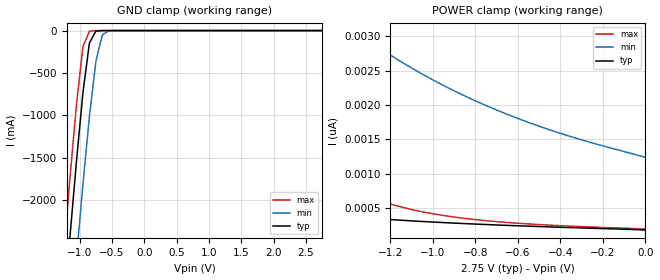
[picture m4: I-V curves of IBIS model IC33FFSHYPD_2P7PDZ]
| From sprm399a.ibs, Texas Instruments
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|   Model IC33FFSHYPD_2P7PDZ
[Model]   IC33FFSHYPD_2P7PDZ
Model_type   Input
Polarity   Non-Inverting
Vinl =   0.8250V
Vinh =   1.9250V
C_comp   2.1397pF   2.1767pF   2.7158pF
[Temperature Range]   25.0000   0.1250k   -40.0000
[Voltage Range]   2.7500V   2.5000V   3.0000V
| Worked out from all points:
|   GND clamp passes 1 mA (typ) near -0.66 V on its own axis
[GND_clamp]
| voltage   I(typ)   I(min)   I(max)
-2.75V    -17.91A    -19.01A    -17.27A
-1.25V    -3.342A    -4.502A    -2.646A
-1.15V    -2.424A    -3.58A     -1.732A
-1.05V    -1.541A    -2.68A     -871.7mA
-950mV    -732.7mA   -1.814A    -188.7mA
-850mV    -147.9mA   -1.014A    -7.751mA
-750mV    -6.008mA   -364.9mA   -798.6uA
-650mV    -206.2uA   -49.97mA   -59.18uA
-550mV    -9.482uA   -3.232mA   -2.615uA
2.75V     180.2pA    1.447nA    169.1pA
[POWER_clamp]
| voltage   I(typ)   I(min)   I(max)
-2.75V    1.397nA    9.158nA    24.63nA
-2.4V     920.9pA    6.881nA    9.413nA
-2V       610.6pA    4.999nA    3.236nA
-1.95V    583.2pA    4.806nA    2.845nA
-1.8V     511.3pA    4.276nA    1.953nA
-1.7V     471pA      3.959nA    1.536nA
-1.55V    420pA      3.532nA    1.094nA
-1.35V    365.5pA    3.042nA    728pA
-1.1V     313.7pA    2.538nA    479pA
-750mV    260.3pA    1.992nA    316.3pA
-400mV    220.4pA    1.587nA    243.2pA
0V        180.2pA    1.238nA    193.4pA
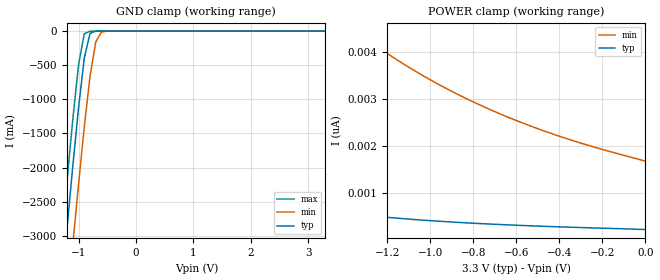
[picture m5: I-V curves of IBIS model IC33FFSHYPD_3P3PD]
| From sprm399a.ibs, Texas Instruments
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|   Model IC33FFSHYPD_3P3PD
[Model]   IC33FFSHYPD_3P3PD
Model_type   Input
Polarity   Non-Inverting
Vinl =   0.9900V
Vinh =   2.3100V
C_comp   2.7290pF   2.5232pF   5.1738pF
[Temperature Range]   25.0000   0.1250k   -40.0000
[Voltage Range]   3.3000V   3.0000V   3.6000V
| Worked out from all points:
|   GND clamp passes 1 mA (typ) near -0.69 V on its own axis
[GND_clamp]
| voltage   I(typ)   I(min)   I(max)
-3.3V     -23.34A    -24.42A    -22.71A
-1.3V     -3.808A    -4.968A    -3.114A
-1.2V     -2.88A     -4.039A    -2.185A
-1.1V     -1.977A    -3.127A    -1.292A
-1V       -1.123A    -2.241A    -489.8mA
-900mV    -393.5mA   -1.402A    -39.32mA
-800mV    -34.1mA    -660.7mA   -2.407mA
-700mV    -1.07mA    -156.4mA   -232.2uA
-600mV    -43.08uA   -13.13mA   -13.27uA
-400mV    -95.63nA   -46.07uA   -11.78nA
3.3V      233.2pA    2.063nA    221.1pA
[POWER_clamp]
| voltage   I(typ)   I(min)   I(max)
-3.3V     6.524nA    22.06nA    NA
-3.05V    4.505nA    17.86nA    NA
-2.8V     3.139nA    14.47nA    NA
-2.6V     2.372nA    12.24nA    NA
-2.3V     1.589nA    9.546nA    NA
-2V       1.097nA    7.465nA    NA
-1.7V     784.5pA    5.861nA    NA
-1.35V    559.4pA    4.448nA    NA
-1.05V    437.9pA    3.535nA    NA
-750mV    355.9pA    2.83nA     NA
-400mV    290.4pA    2.209nA    NA
0V        233.2pA    1.682nA    NA
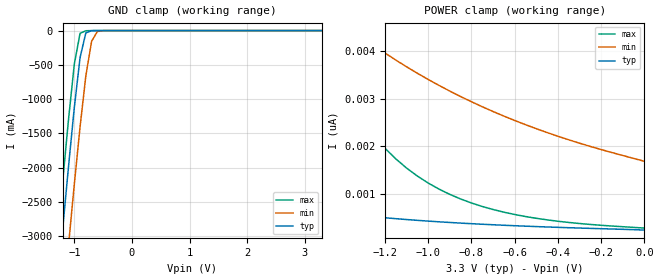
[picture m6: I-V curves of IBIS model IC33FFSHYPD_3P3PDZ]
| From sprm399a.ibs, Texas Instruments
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|   Model IC33FFSHYPD_3P3PDZ
[Model]   IC33FFSHYPD_3P3PDZ
Model_type   Input
Polarity   Non-Inverting
Vinl =   0.9900V
Vinh =   2.3100V
C_comp   2.7290pF   2.5232pF   5.1738pF
[Temperature Range]   25.0000   0.1250k   -40.0000
[Voltage Range]   3.3000V   3.0000V   3.6000V
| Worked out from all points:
|   GND clamp passes 1 mA (typ) near -0.69 V on its own axis
[GND_clamp]
| voltage   I(typ)   I(min)   I(max)
-3.3V     -23.34A    -24.42A    -22.71A
-1.3V     -3.808A    -4.968A    -3.114A
-1.2V     -2.88A     -4.039A    -2.185A
-1.1V     -1.977A    -3.127A    -1.292A
-1V       -1.123A    -2.241A    -489.8mA
-900mV    -393.5mA   -1.402A    -39.31mA
-800mV    -34.1mA    -660.7mA   -2.406mA
-700mV    -1.07mA    -156.4mA   -232.2uA
-600mV    -43.05uA   -13.13mA   -13.27uA
-400mV    -95.62nA   -45.97uA   -11.78nA
3.3V      231.2pA    2.06nA     219pA
[POWER_clamp]
| voltage   I(typ)   I(min)   I(max)
-3.3V     6.522nA    22.06nA    577.8nA
-3.05V    4.503nA    17.86nA    293.1nA
-2.7V     2.724nA    13.31nA    112.3nA
-2.35V    1.693nA    9.946nA    42.79nA
-2V       1.094nA    7.463nA    16.29nA
-1.55V    672.1pA    5.2nA      4.797nA
-1.5V     640.3pA    4.999nA    4.202nA
-1.35V    557.4pA    4.445nA    2.845nA
-1.25V    511.3pA    4.114nA    2.21nA
-1V       420pA      3.402nA    1.221nA
-600mV    322.9pA    2.538nA    559.1pA
0V        231.2pA    1.679nA    272.9pA
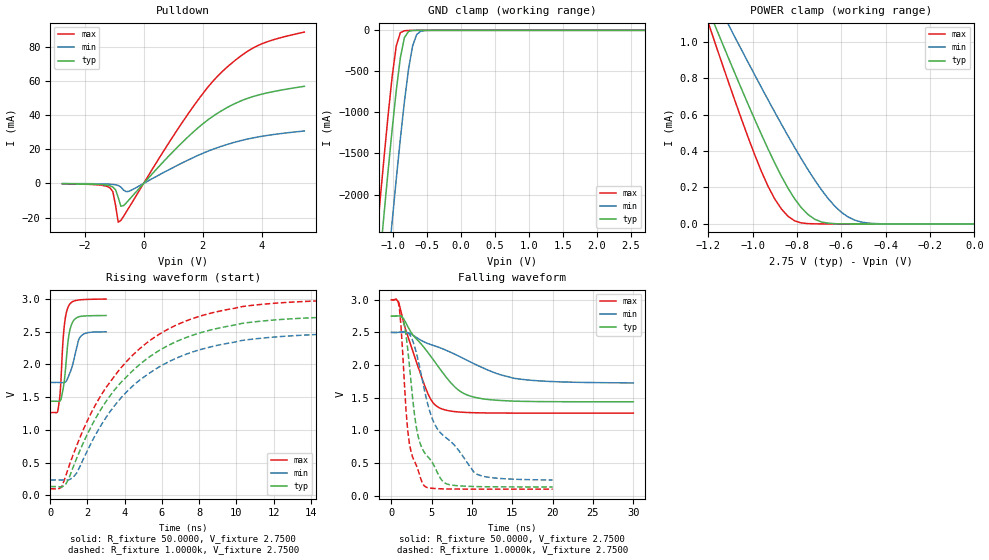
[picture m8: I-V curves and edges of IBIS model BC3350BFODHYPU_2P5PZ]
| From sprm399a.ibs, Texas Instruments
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|   Model BC3350BFODHYPU_2P5PZ
[Model]   BC3350BFODHYPU_2P5PZ
Model_type   I/O_open_drain
Polarity   Non-Inverting
Enable   Active-Low
Vinl =   0.7500V
Vinh =   1.7500V
Vmeas =   1.2500V
Cref =  15.0000pF
Rref = 100.0000M
Vref =  0.000V
C_comp   2.5179pF   2.5239pF   3.1043pF
[Temperature Range]   25.0000   0.1250k   -40.0000
[Voltage Range]   2.7500V   2.5000V   3.0000V
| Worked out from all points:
|   slope of the pulldown table from 0 to 0.412 V, typ, clamps not added: 52.2 ohm
|   GND clamp passes 1 mA (typ) near -0.68 V on its own axis
|   POWER clamp passes 1 mA (typ) near -1.14 V on its own axis
|   rising waveform, R_fixture 50.0000, V_fixture 2.7500: 20-80 % time 293ps typ, 424ps min, 236ps max; typ from 1.44 V to 2.75 V
|   rising waveform, R_fixture 1.0000k, V_fixture 2.7500: 20-80 % time 4.36ns typ, 4.36ns min, 4.3ns max; typ from 0.135 V to 2.74 V
|   falling waveform, R_fixture 50.0000, V_fixture 2.7500: 20-80 % time 5.07ns typ, 8.6ns min, 2.85ns max; typ from 2.75 V to 1.44 V
|   falling waveform, R_fixture 1.0000k, V_fixture 2.7500: 20-80 % time 2.08ns typ, 4.99ns min, 1.15ns max; typ from 2.75 V to 0.135 V
[Pulldown]
| voltage   I(typ)   I(min)   I(max)
-2.75V    -196uA     -89uA      -273uA
-1.13V    -1.446mA   -462.7uA   -2.767mA
-1.04V    -2.119mA   -590.9uA   -4.941mA
-950mV    -3.685mA   -805.5uA   -12.8mA
-860mV    -8.252mA   -1.217mA   -22.69mA
-770mV    -13.34mA   -2.137mA   -21.65mA
-680mV    -13.04mA   -3.916mA   -19.29mA
-410mV    -7.97mA    -3.938mA   -11.68mA
1.3V      23.88mA    11.95mA    35.5mA
2.56V     41.71mA    21.31mA    63.75mA
3.82V     51.42mA    27.03mA    80.29mA
5.44V     56.82mA    30.68mA    88.57mA
[GND_clamp]
| voltage   I(typ)   I(min)   I(max)
-2.75V    -17.91A    -19.01A    -17.27A
-1.25V    -3.342A    -4.502A    -2.647A
-1.19V    -2.788A    -3.947A    -2.094A
-1.13V    -2.244A    -3.398A    -1.555A
-1.01V    -1.205A    -2.328A    -562.5mA
-950mV    -733.5mA   -1.814A    -190.1mA
-890mV    -336.3mA   -1.323A    -28.95mA
-830mV    -88.34mA   -867.9mA   -5.22mA
-770mV    -13.12mA   -475.3mA   -1.386mA
-710mV    -1.827mA   -190.8mA   -326.2uA
-590mV    -39.46uA   -10.65mA   -10.29uA
2.71V     264.7pA    4.348nA    254.9pA
[POWER_clamp]
| voltage   I(typ)   I(min)   I(max)
-2.73V    5.917mA    5.089mA    6.919mA
-1.2V     1.179mA    1.31mA     1.105mA
-1.17V    1.09mA     1.238mA    996.2uA
-1.11V    914uA      1.096mA    782.5uA
-1.08V    827uA      1.026mA    677.7uA
-990mV    572.4uA    816.8uA    378.4uA
-900mV    334.2uA    613.4uA    137uA
-810mV    137.3uA    418.9uA    16.8uA
-720mV    26.09uA    241.1uA    664.2nA
-600mV    534.9nA    64.48uA    19.7nA
-510mV    25.5nA     10.6uA     1.291nA
0V        271.3pA    1.545nA    292.4pA
[Ramp]
| variable   typ   min   max
dV/dt_r   0.2317n/0.1893f  33.7855p/0.3440n   0.1839n/0.1188f
dV/dt_f   0.7869/5.0163n   0.4633/8.5159n   1.0409/2.8255n
R_load = 50.0000
[Rising Waveform]
R_fixture = 50.0000
V_fixture = 2.7500
V_fixture_min = 2.5000
V_fixture_max = 3.0000
| time   V(typ)   V(min)   V(max)
0s        1.438V     1.725V     1.265V
424.2ps   1.436V     1.725V     1.319V
545.5ps   1.448V     1.724V     1.617V
666.7ps   1.593V     1.722V     2.285V
727.3ps   1.691V     1.722V     2.516V
818.2ps   1.928V     1.732V     2.725V
969.7ps   2.388V     1.812V     2.884V
1.212ns   2.652V     2.008V     2.961V
1.636ns   2.733V     2.428V     2.987V
3ns       2.747V     2.498V     2.998V
[Rising Waveform]
R_fixture = 1.0000k
V_fixture = 2.7500
V_fixture_min = 2.5000
V_fixture_max = 3.0000
| time   V(typ)   V(min)   V(max)
0s        134.8mV    236.4mV    101.3mV
606.1ps   128.5mV    236.5mV    124.7mV
808.1ps   156.8mV    234.3mV    279.7mV
1.212ns   418.4mV    271.3mV    608.1mV
2.222ns   1.066V     814.6mV    1.273V
3.434ns   1.604V     1.363V     1.816V
4.848ns   2.01V      1.77V      2.251V
6.465ns   2.307V     2.055V     2.558V
10.91ns   2.648V     2.387V     2.904V
20ns      2.744V     2.491V     2.995V
[Falling Waveform]
R_fixture = 50.0000
V_fixture = 2.7500
V_fixture_min = 2.5000
V_fixture_max = 3.0000
| time   V(typ)   V(min)   V(max)
0s        2.75V      2.5V       3V
909.1ps   2.753V     2.502V     2.963V
1.818ns   2.644V     2.5V       2.524V
4.242ns   2.241V     2.345V     1.651V
5.152ns   2.091V     2.304V     1.427V
6.061ns   1.936V     2.264V     1.339V
8.485ns   1.603V     2.129V     1.282V
11.21ns   1.486V     1.965V     1.269V
16.67ns   1.445V     1.776V     1.265V
30ns      1.438V     1.728V     1.265V
[Falling Waveform]
R_fixture = 1.0000k
V_fixture = 2.7500
V_fixture_min = 2.5000
V_fixture_max = 3.0000
| time   V(typ)   V(min)   V(max)
0s        2.75V      2.5V       3V
1.01ns    2.762V     2.503V     2.859V
1.616ns   2.617V     2.51V      1.728V
2.222ns   2.019V     2.476V     812.9mV
3.03ns    1.102V     2.22V      485.3mV
4.04ns    674.1mV    1.654V     157.4mV
5.657ns   368.4mV    1.035V     109.5mV
6.869ns   182mV      880.4mV    104.9mV
10.3ns    141.5mV    354.1mV    101.8mV
20ns      135mV      241.6mV    101.3mV
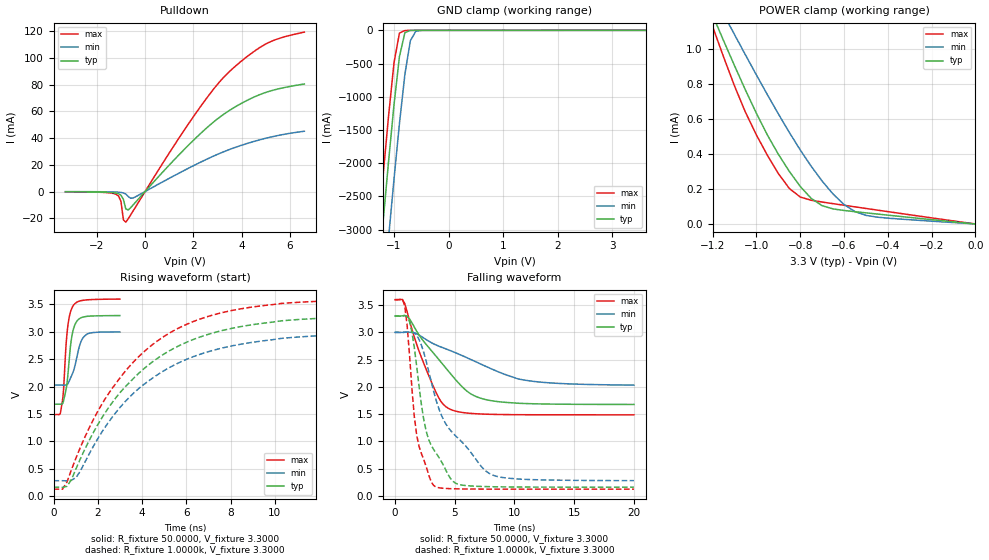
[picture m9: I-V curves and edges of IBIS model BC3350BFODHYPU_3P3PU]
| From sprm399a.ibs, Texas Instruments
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|   Model BC3350BFODHYPU_3P3PU
[Model]   BC3350BFODHYPU_3P3PU
Model_type   I/O_open_drain
Polarity   Non-Inverting
Enable   Active-Low
Vinl =   0.9900V
Vinh =   2.3100V
Vmeas =   1.6500V
Cref =  15.0000pF
Rref = 100.0000M
Vref =  0.000V
C_comp   3.1345pF   2.9748pF   5.4957pF
[Temperature Range]   25.0000   0.1250k   -40.0000
[Voltage Range]   3.3000V   3.0000V   3.6000V
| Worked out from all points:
|   slope of the pulldown table from 0 to 0.495 V, typ, clamps not added: 49.9 ohm
|   GND clamp passes 1 mA (typ) near -0.66 V on its own axis
|   POWER clamp passes 1 mA (typ) near -1.13 V on its own axis
|   rising waveform, R_fixture 50.0000, V_fixture 3.3000: 20-80 % time 267ps typ, 384ps min, 224ps max; typ from 1.68 V to 3.3 V
|   rising waveform, R_fixture 1.0000k, V_fixture 3.3000: 20-80 % time 3.97ns typ, 4.07ns min, 3.81ns max; typ from 0.162 V to 3.3 V
|   falling waveform, R_fixture 50.0000, V_fixture 3.3000: 20-80 % time 3.68ns typ, 6.15ns min, 2.15ns max; typ from 3.3 V to 1.68 V
|   falling waveform, R_fixture 1.0000k, V_fixture 3.3000: 20-80 % time 1.78ns typ, 3.63ns min, 1.05ns max; typ from 3.3 V to 0.162 V
[Pulldown]
| voltage   I(typ)   I(min)   I(max)
-3.3V     -159uA     -74uA      -216uA
-1.2V     -1.209mA   -418.8uA   -2.097mA
-1V       -2.765mA   -711.7uA   -7.396mA
-900mV    -5.896mA   -1.056mA   -21.15mA
-800mV    -13.01mA   -1.838mA   -22.95mA
-700mV    -13.84mA   -3.683mA   -20.42mA
-500mV    -10.11mA   -4.828mA   -14.63mA
1.7V      32.91mA    16.52mA    48.03mA
3.2V      57.06mA    29.34mA    84.35mA
4.1V      67.02mA    35.22mA    99.18mA
5V        74.15mA    39.85mA    110.4mA
6.6V      80.46mA    45.12mA    119.3mA
[GND_clamp]
| voltage   I(typ)   I(min)   I(max)
-3.3V     -23.34A    -24.42A    -22.71A
-1.3V     -3.808A    -4.968A    -3.114A
-1.2V     -2.88A     -4.039A    -2.186A
-1.1V     -1.977A    -3.127A    -1.292A
-1V       -1.123A    -2.241A    -490.8mA
-900mV    -394.6mA   -1.403A    -40.99mA
-800mV    -35.51mA   -661.5mA   -2.889mA
-700mV    -1.457mA   -157.5mA   -462.5uA
-600mV    -189.6uA   -13.98mA   -225uA
-400mV    -135.5uA   -145.8uA   -210.3uA
3.62V     0A         0A         0A
[POWER_clamp]
| voltage   I(typ)   I(min)   I(max)
-3.3V     7.712mA    6.522mA    9.121mA
-1.2V     1.191mA    1.315mA    1.126mA
-1.15V    1.045mA    1.197mA    952.4uA
-1.1V     902.5uA    1.08mA     787uA
-1V       630.6uA    849.8uA    507.3uA
-900mV    397.7uA    628uA      287.6uA
-850mV    300uA      522.4uA    202.7uA
-750mV    145.8uA    329.1uA    135.2uA
-650mV    85.85uA    170.4uA    115.8uA
-550mV    69.94uA    70.52uA    97.52uA
-450mV    56.73uA    38.93uA    79.36uA
0V        339.2pA    2.034nA    390pA
[Ramp]
| variable   typ   min   max
dV/dt_r   2.0284m/0.4301n   0.8263m/0.3985n   3.7339m/0.4501n
dV/dt_f   0.9733/3.6469n   0.5839/6.1478n   1.2669/2.1300n
R_load = 50.0000
[Rising Waveform]
R_fixture = 50.0000
V_fixture = 3.3000
V_fixture_min = 3.0000
V_fixture_max = 3.6000
| time   V(typ)   V(min)   V(max)
0s        1.678V     2.026V     1.488V
333.3ps   1.676V     2.026V     1.564V
454.5ps   1.738V     2.025V     1.951V
545.5ps   1.905V     2.026V     2.631V
636.4ps   2.159V     2.044V     3.074V
757.6ps   2.704V     2.147V     3.349V
878.8ps   3.016V     2.258V     3.47V
1.212ns   3.25V      2.791V     3.566V
1.424ns   3.277V     2.929V     3.58V
3ns       3.297V     2.997V     3.598V
[Rising Waveform]
R_fixture = 1.0000k
V_fixture = 3.3000
V_fixture_min = 3.0000
V_fixture_max = 3.6000
| time   V(typ)   V(min)   V(max)
0s        161.7mV    279.7mV    125.2mV
404ps     157.5mV    279.9mV    125.1mV
606.1ps   176.3mV    276.5mV    254.2mV
1.01ns    492.5mV    334.1mV    689mV
2.02ns    1.318V     1.061V     1.562V
3.232ns   1.991V     1.722V     2.274V
4.444ns   2.442V     2.145V     2.757V
6.061ns   2.817V     2.505V     3.144V
10.3ns    3.201V     2.88V      3.518V
20ns      3.297V     2.993V     3.598V
[Falling Waveform]
R_fixture = 50.0000
V_fixture = 3.3000
V_fixture_min = 3.0000
V_fixture_max = 3.6000
| time   V(typ)   V(min)   V(max)
0s        3.3V       3V         3.6V
808.1ps   3.304V     3.002V     3.531V
1.818ns   3.019V     2.974V     2.776V
3.232ns   2.616V     2.79V      1.995V
3.838ns   2.457V     2.732V     1.736V
4.646ns   2.242V     2.664V     1.587V
6.263ns   1.884V     2.511V     1.516V
8.081ns   1.747V     2.33V      1.497V
11.72ns   1.691V     2.099V     1.49V
20ns      1.678V     2.033V     1.488V
[Falling Waveform]
R_fixture = 1.0000k
V_fixture = 3.3000
V_fixture_min = 3.0000
V_fixture_max = 3.6000
| time   V(typ)   V(min)   V(max)
0s        3.3V       3V         3.6V
808.1ps   3.312V     3.003V     3.491V
1.212ns   3.2V       3.01V      2.591V
1.616ns   2.719V     2.991V     1.449V
1.818ns   2.37V      2.946V     1.109V
2.424ns   1.377V     2.619V     656.3mV
3.232ns   851.5mV    1.92V      192.6mV
5.051ns   237mV      1.107V     131.7mV
8.081ns   170.1mV    392.5mV    126.1mV
20ns      161.8mV    281.5mV    125.2mV
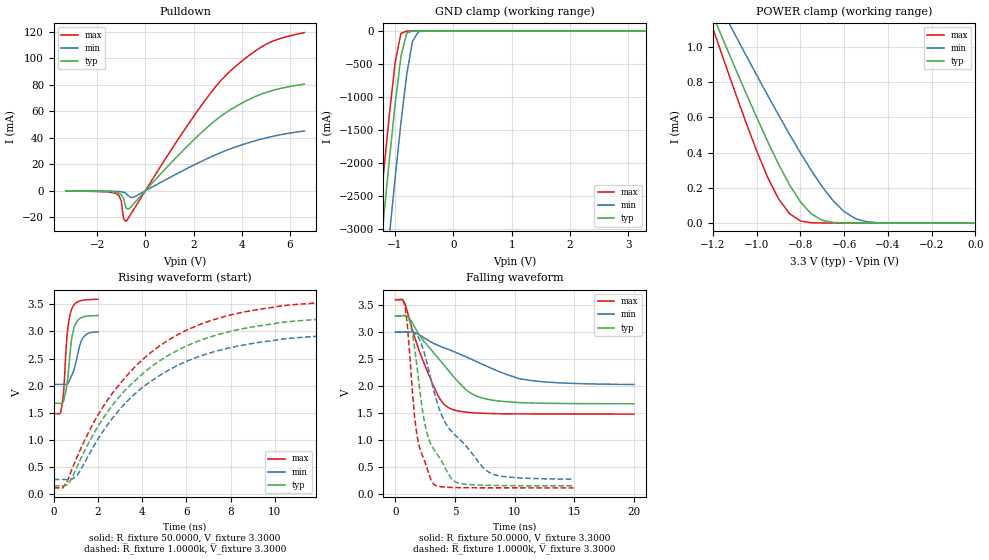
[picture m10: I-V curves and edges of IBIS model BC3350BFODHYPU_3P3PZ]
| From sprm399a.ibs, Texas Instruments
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|   Model BC3350BFODHYPU_3P3PZ
[Model]   BC3350BFODHYPU_3P3PZ
Model_type   I/O_open_drain
Polarity   Non-Inverting
Enable   Active-Low
Vinl =   0.9900V
Vinh =   2.3100V
Vmeas =   1.6500V
Cref =  15.0000pF
Rref = 100.0000M
Vref =  0.000V
C_comp   3.1345pF   2.9748pF   5.4957pF
[Temperature Range]   25.0000   0.1250k   -40.0000
[Voltage Range]   3.3000V   3.0000V   3.6000V
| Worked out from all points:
|   slope of the pulldown table from 0 to 0.495 V, typ, clamps not added: 49.9 ohm
|   GND clamp passes 1 mA (typ) near -0.67 V on its own axis
|   POWER clamp passes 1 mA (typ) near -1.14 V on its own axis
|   rising waveform, R_fixture 50.0000, V_fixture 3.3000: 20-80 % time 267ps typ, 381ps min, 224ps max; typ from 1.68 V to 3.29 V
|   rising waveform, R_fixture 1.0000k, V_fixture 3.3000: 20-80 % time 4.3ns typ, 4.29ns min, 4.24ns max; typ from 0.155 V to 3.29 V
|   falling waveform, R_fixture 50.0000, V_fixture 3.3000: 20-80 % time 3.68ns typ, 6.15ns min, 2.15ns max; typ from 3.3 V to 1.68 V
|   falling waveform, R_fixture 1.0000k, V_fixture 3.3000: 20-80 % time 1.73ns typ, 3.57ns min, 1.02ns max; typ from 3.3 V to 0.156 V
[Pulldown]
| voltage   I(typ)   I(min)   I(max)
-3.3V     -159uA     -74uA      -215uA
-1.2V     -1.209mA   -418.8uA   -2.097mA
-1V       -2.765mA   -711.8uA   -7.394mA
-900mV    -5.895mA   -1.056mA   -21.15mA
-800mV    -13mA      -1.838mA   -22.95mA
-700mV    -13.84mA   -3.683mA   -20.42mA
-500mV    -10.11mA   -4.828mA   -14.63mA
1.7V      32.91mA    16.52mA    48.03mA
3.2V      57.06mA    29.34mA    84.35mA
4.1V      67.02mA    35.22mA    99.19mA
5V        74.15mA    39.85mA    110.4mA
6.6V      80.46mA    45.12mA    119.3mA
[GND_clamp]
| voltage   I(typ)   I(min)   I(max)
-3.3V     -23.34A    -24.42A    -22.71A
-1.3V     -3.808A    -4.968A    -3.114A
-1.2V     -2.88A     -4.039A    -2.186A
-1.1V     -1.977A    -3.127A    -1.292A
-1V       -1.123A    -2.241A    -490.7mA
-900mV    -394.6mA   -1.403A    -40.81mA
-800mV    -35.4mA    -661.4mA   -2.68mA
-700mV    -1.323mA   -157.5mA   -251.4uA
-600mV    -53.86uA   -13.9mA    -14.12uA
-400mV    -110.6nA   -62.84uA   -12.31nA
3.3V      340.8pA    35.66nA    327pA
[POWER_clamp]
| voltage   I(typ)   I(min)   I(max)
-3.3V     7.71mA     6.521mA    9.119mA
-1.2V     1.179mA    1.31mA     1.105mA
-1.15V    1.031mA    1.191mA    924.5uA
-1.1V     884.9uA    1.073mA    747.4uA
-950mV    463.6uA    725.5uA    259.4uA
-900mV    334.2uA    613.4uA    137uA
-850mV    216.9uA    503.9uA    53.53uA
-800mV    120.1uA    398.1uA    11.85uA
-700mV    15.1uA     205.4uA    362.5nA
-600mV    535nA      64.48uA    20nA
-550mV    96.74nA    26.14uA    4.477nA
0V        340.8pA    2.036nA    391.7pA
[Ramp]
| variable   typ   min   max
dV/dt_r   0.2240n/0.1170f  0.1219n/0.1041f  0.1534n/4.2679n
dV/dt_f   0.9752/3.6442n   0.5851/6.1456n   1.2694/2.1275n
R_load = 50.0000
[Rising Waveform]
R_fixture = 50.0000
V_fixture = 3.3000
V_fixture_min = 3.0000
V_fixture_max = 3.6000
| time   V(typ)   V(min)   V(max)
|  0.000S   1.6747V   2.0242V   1.4843V
30.3ps    1.675V     2.024V     1.484V
303ps     1.673V     2.024V     1.501V
393.9ps   1.679V     2.023V     1.71V
454.5ps   1.735V     2.022V     1.945V
545.5ps   1.901V     2.023V     2.625V
606.1ps   2.046V     2.031V     2.952V
787.9ps   2.804V     2.172V     3.386V
969.7ps   3.127V     2.379V     3.514V
1.303ns   3.264V     2.87V      3.573V
2ns       3.292V     2.992V     3.592V
[Rising Waveform]
R_fixture = 1.0000k
V_fixture = 3.3000
V_fixture_min = 3.0000
V_fixture_max = 3.6000
| time   V(typ)   V(min)   V(max)
0s        155.4mV    272.2mV    118.3mV
404ps     151.2mV    272.5mV    116.9mV
606.1ps   168.3mV    269mV      236.1mV
1.01ns    470mV      324.2mV    646.5mV
2.02ns    1.264V     1.03V      1.474V
3.232ns   1.919V     1.676V     2.152V
4.646ns   2.418V     2.15V      2.692V
6.263ns   2.777V     2.491V     3.069V
10.71ns   3.183V     2.873V     3.488V
20ns      3.294V     2.99V      3.595V
[Falling Waveform]
R_fixture = 50.0000
V_fixture = 3.3000
V_fixture_min = 3.0000
V_fixture_max = 3.6000
| time   V(typ)   V(min)   V(max)
0s        3.3V       3V         3.6V
808.1ps   3.304V     3.002V     3.531V
1.818ns   3.018V     2.974V     2.772V
3.232ns   2.614V     2.789V     1.99V
3.838ns   2.454V     2.732V     1.731V
4.646ns   2.239V     2.663V     1.583V
6.263ns   1.881V     2.51V      1.512V
8.081ns   1.744V     2.328V     1.493V
11.72ns   1.687V     2.097V     1.485V
20ns      1.675V     2.031V     1.484V
[Falling Waveform]
R_fixture = 1.0000k
V_fixture = 3.3000
V_fixture_min = 3.0000
V_fixture_max = 3.6000
| time   V(typ)   V(min)   V(max)
0s        3.3V       3V         3.6V
808.1ps   3.312V     3.003V     3.491V
1.212ns   3.2V       3.01V      2.58V
1.616ns   2.714V     2.991V     1.426V
1.818ns   2.36V      2.945V     1.085V
2.424ns   1.357V     2.615V     632.8mV
3.232ns   828.7mV    1.907V     182.7mV
5.051ns   227.2mV    1.087V     124.6mV
7.879ns   164.4mV    403.9mV    119.3mV
14.95ns   155.8mV    279.1mV    118.3mV
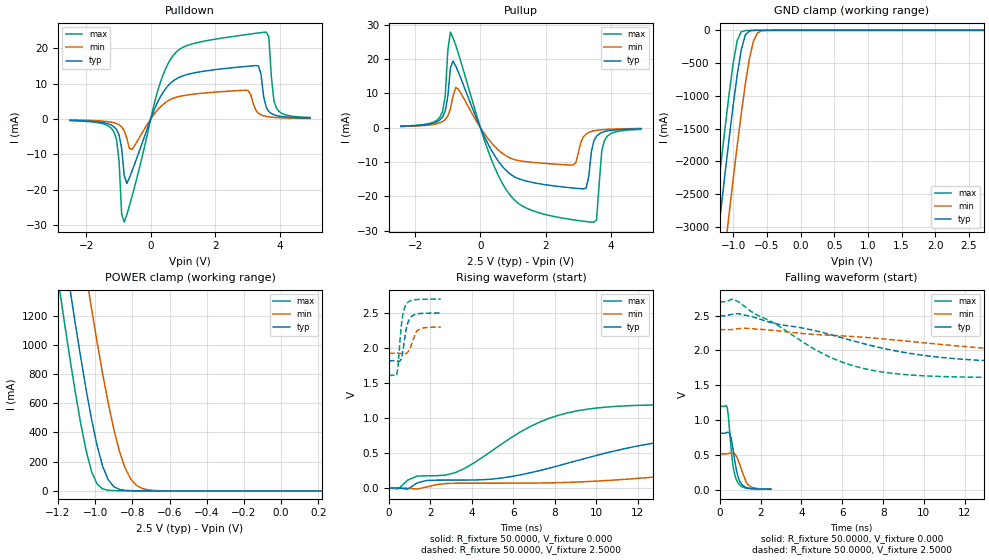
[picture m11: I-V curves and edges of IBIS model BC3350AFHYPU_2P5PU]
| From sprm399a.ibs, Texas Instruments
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|   Model BC3350AFHYPU_2P5PU
[Model]   BC3350AFHYPU_2P5PU
Model_type   I/O
Polarity   Non-Inverting
Enable   Active-Low
Vinl =   0.7500V
Vinh =   1.7500V
Vmeas =   1.2500V
Cref =  15.0000pF
Rref = 100.0000M
Vref =  0.000V
C_comp   2.5606pF   2.5670pF   2.5554pF
[Temperature Range]   25.0000   0.1250k   -40.0000
[Voltage Range]   2.5000V   2.3000V   2.7000V
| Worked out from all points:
|   slope of the pulldown table from 0 to 0.375 V, typ, clamps not added: 50.5 ohm
|   slope of the pullup table from 0 to 0.375 V, typ, clamps not added: 52.4 ohm
|   GND clamp passes 1 mA (typ) near -0.69 V on its own axis
|   POWER clamp passes 1 mA (typ) near -0.78 V on its own axis
|   rising waveform, R_fixture 50.0000, V_fixture 0.000: 20-80 % time 7.03ns typ, 12.5ns min, 4.06ns max; typ from 0.001 V to 0.809 V
|   rising waveform, R_fixture 50.0000, V_fixture 2.5000: 20-80 % time 245ps typ, 281ps min, 211ps max; typ from 1.82 V to 2.5 V
|   falling waveform, R_fixture 50.0000, V_fixture 0.000: 20-80 % time 303ps typ, 381ps min, 259ps max; typ from 0.809 V to 0.005 V
|   falling waveform, R_fixture 50.0000, V_fixture 2.5000: 20-80 % time 6.26ns typ, 9.67ns min, 4ns max; typ from 2.5 V to 1.82 V
[Pulldown]
| voltage   I(typ)   I(min)   I(max)
-2.5V     -374uA     -257uA     -456uA
-1.14V    -2.171mA   -1.061mA   -3.627mA
-980mV    -4.503mA   -1.644mA   -11.87mA
-820mV    -15.98mA   -3.315mA   -29.14mA
-580mV    -14.72mA   -8.608mA   -21.9mA
300mV     6.273mA    3.423mA    10.36mA
940mV     12mA       6.481mA    19.96mA
3.02V     14.92mA    8.019mA    23.92mA
3.34V     15mA       1.628mA    24.32mA
3.58V     3.34mA     742.8uA    24.56mA
3.9V      981uA      418uA      3.045mA
4.94V     280uA      169uA      430uA
[Pullup]
| voltage   I(typ)   I(min)   I(max)
-2.44V    429uA      355uA      471uA
-1.24V    2.302mA    1.467mA    3.141mA
-1.08V    4.893mA    2.412mA    9.263mA
-920mV    17.47mA    5.496mA    27.87mA
-680mV    16.28mA    11.27mA    21.75mA
440mV     -8.176mA   -5.47mA    -11.64mA
1.4V      -15.51mA   -9.865mA   -23.35mA
2.84V     -17.54mA   -10.83mA   -26.8mA
3.24V     -17.6mA    -1.801mA   -27.32mA
3.48V     -3.754mA   -895.8uA   -27.51mA
3.8V      -1.135mA   -524.2uA   -3.76mA
4.92V     -310uA     -210uA     -458uA
[GND_clamp]
| voltage   I(typ)   I(min)   I(max)
-2.5V     -15.48A    -16.59A    -14.82A
-1.3V     -3.836A    -5.005A    -3.135A
-1.24V    -3.276A    -4.446A    -2.575A
-1.18V    -2.724A    -3.891A    -2.024A
-1.12V    -2.181A    -3.344A    -1.486A
-1.06V    -1.653A    -2.804A    -972.8mA
-940mV    -681.3mA   -1.763A    -154.8mA
-880mV    -296.6mA   -1.275A    -21.34mA
-820mV    -70.8mA    -824.4mA   -4.046mA
-700mV    -1.244mA   -169.1mA   -348.3uA
-580mV    -94.36uA   -8.425mA   -115.6uA
2.72V     0A         0A         0A
[POWER_clamp]
| voltage   I(typ)   I(min)   I(max)
-2.49V    14.32A     15.09A     13.9A
-1.2V     1.938A     2.775A     1.451A
-1.17V    1.676A     2.51A      1.19A
-1.14V    1.419A     2.247A     938.4mA
-1.11V    1.169A     1.989A     698.1mA
-1.05V    700.4mA    1.489A     281.6mA
-1.02V    491.6mA    1.249A     133.5mA
-960mV    168.5mA    801.5mA    14.02mA
-930mV    76mA       600.7mA    4.535mA
-840mV    3.983mA    158.9mA    893.4uA
-780mV    921.1uA    39.8mA     480.6uA
220mV     0A         0A         0A
[Ramp]
| variable   typ   min   max
dV/dt_r   0.2848/7.3030n   60.7008m/6.6251n  0.6851/3.7184n
dV/dt_f   0.3451/5.0572n   0.1157/5.2443n   0.6386/3.8070n
R_load = 50.0000
[Rising Waveform]
R_fixture = 50.0000
V_fixture = 0.000
V_fixture_min = 0.000
V_fixture_max = 0.000
| time   V(typ)   V(min)   V(max)
0s        1.49mV     1.262mV    1.706mV
454.5ps   2.168mV    1.584mV    -9.699mV
1.364ns   75.35mV    -11.7mV    172.1mV
3.182ns   115.4mV    70.43mV    220.2mV
7.727ns   285.4mV    76.01mV    996.2mV
10.45ns   500.7mV    108.5mV    1.156V
14.09ns   697.7mV    192.6mV    1.192V
18.64ns   784.6mV    317.2mV    1.195V
27.73ns   808.2mV    470.5mV    1.195V
45ns      809.1mV    511.9mV    1.195V
[Rising Waveform]
R_fixture = 50.0000
V_fixture = 2.5000
V_fixture_min = 2.3000
V_fixture_max = 2.7000
| time   V(typ)   V(min)   V(max)
0s        1.816V     1.924V     1.609V
378.8ps   1.814V     1.924V     1.624V
454.5ps   1.809V     1.924V     1.777V
555.6ps   1.821V     1.922V     2.18V
631.3ps   1.886V     1.92V      2.392V
732.3ps   2.067V     1.917V     2.546V
858.6ps   2.299V     1.925V     2.631V
1.061ns   2.439V     2.023V     2.675V
1.389ns   2.487V     2.25V      2.69V
2.5ns     2.497V     2.297V     2.697V
[Falling Waveform]
R_fixture = 50.0000
V_fixture = 0.000
V_fixture_min = 0.000
V_fixture_max = 0.000
| time   V(typ)   V(min)   V(max)
0s        809.1mV    513.8mV    1.195V
353.5ps   819mV      514.9mV    1.191V
429.3ps   823.1mV    518.5mV    1.038V
505.1ps   794.1mV    522.8mV    779.3mV
656.6ps   572.2mV    524mV      332.3mV
757.6ps   383.5mV    503.9mV    191.9mV
883.8ps   198.6mV    436.5mV    102.2mV
1.086ns   74.01mV    270.8mV    41.99mV
1.414ns   19.98mV    62.24mV    13.98mV
2.5ns     5.319mV    5.064mV    5.445mV
[Falling Waveform]
R_fixture = 50.0000
V_fixture = 2.5000
V_fixture_min = 2.3000
V_fixture_max = 2.7000
| time   V(typ)   V(min)   V(max)
0s        2.5V       2.3V       2.7V
606.1ps   2.521V     2.3V       2.739V
909.1ps   2.53V      2.314V     2.702V
2.727ns   2.386V     2.286V     2.381V
4.546ns   2.293V     2.232V     2.036V
5.758ns   2.201V     2.213V     1.859V
8.182ns   2.019V     2.162V     1.681V
11.21ns   1.89V      2.076V     1.623V
15.15ns   1.831V     1.988V     1.61V
30ns      1.816V     1.925V     1.609V
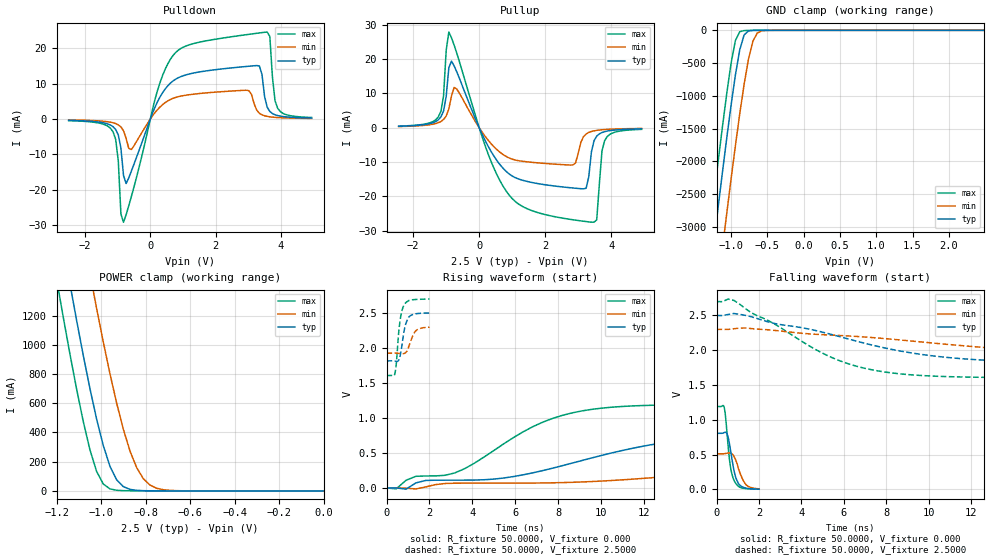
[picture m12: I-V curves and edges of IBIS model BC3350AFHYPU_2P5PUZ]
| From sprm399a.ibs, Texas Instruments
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|   Model BC3350AFHYPU_2P5PUZ
[Model]   BC3350AFHYPU_2P5PUZ
Model_type   I/O
Polarity   Non-Inverting
Enable   Active-Low
Vinl =   0.7500V
Vinh =   1.7500V
Vmeas =   1.2500V
Cref =  15.0000pF
Rref = 100.0000M
Vref =  0.000V
C_comp   2.5606pF   2.5670pF   2.5554pF
[Temperature Range]   25.0000   0.1250k   -40.0000
[Voltage Range]   2.5000V   2.3000V   2.7000V
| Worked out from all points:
|   slope of the pulldown table from 0 to 0.375 V, typ, clamps not added: 50.5 ohm
|   slope of the pullup table from 0 to 0.375 V, typ, clamps not added: 52.4 ohm
|   GND clamp passes 1 mA (typ) near -0.69 V on its own axis
|   POWER clamp passes 1 mA (typ) near -0.79 V on its own axis
|   rising waveform, R_fixture 50.0000, V_fixture 0.000: 20-80 % time 7.01ns typ, 12.4ns min, 4.04ns max; typ from 0 V to 0.806 V
|   rising waveform, R_fixture 50.0000, V_fixture 2.5000: 20-80 % time 243ps typ, 289ps min, 211ps max; typ from 1.81 V to 2.5 V
|   falling waveform, R_fixture 50.0000, V_fixture 0.000: 20-80 % time 300ps typ, 378ps min, 257ps max; typ from 0.806 V to 0.004 V
|   falling waveform, R_fixture 50.0000, V_fixture 2.5000: 20-80 % time 6.26ns typ, 9.37ns min, 4ns max; typ from 2.5 V to 1.81 V
[Pulldown]
| voltage   I(typ)   I(min)   I(max)
-2.5V     -374uA     -257uA     -455uA
-1.14V    -2.171mA   -1.061mA   -3.627mA
-980mV    -4.503mA   -1.644mA   -11.87mA
-820mV    -15.98mA   -3.314mA   -29.14mA
-580mV    -14.72mA   -8.608mA   -21.9mA
300mV     6.272mA    3.423mA    10.36mA
940mV     12mA       6.481mA    19.96mA
3.02V     14.92mA    8.019mA    23.92mA
3.34V     15mA       1.628mA    24.32mA
3.58V     3.34mA     742.8uA    24.56mA
3.9V      980.9uA    418uA      3.045mA
4.94V     280uA      169uA      430uA
[Pullup]
| voltage   I(typ)   I(min)   I(max)
-2.44V    429uA      356uA      472uA
-1.24V    2.302mA    1.467mA    3.141mA
-1.08V    4.893mA    2.412mA    9.262mA
-920mV    17.47mA    5.496mA    27.87mA
-680mV    16.28mA    11.27mA    21.75mA
440mV     -8.177mA   -5.47mA    -11.64mA
1.4V      -15.51mA   -9.865mA   -23.35mA
2.84V     -17.54mA   -10.83mA   -26.8mA
3.24V     -17.6mA    -1.801mA   -27.32mA
3.48V     -3.754mA   -895.8uA   -27.51mA
3.8V      -1.135mA   -524.1uA   -3.76mA
4.92V     -311uA     -209uA     -458uA
[GND_clamp]
| voltage   I(typ)   I(min)   I(max)
-2.5V     -15.48A    -16.59A    -14.82A
-1.3V     -3.836A    -5.005A    -3.135A
-1.24V    -3.276A    -4.446A    -2.575A
-1.18V    -2.724A    -3.891A    -2.024A
-1.12V    -2.181A    -3.344A    -1.486A
-1.06V    -1.653A    -2.804A    -972.7mA
-940mV    -681.3mA   -1.763A    -154.7mA
-880mV    -296.6mA   -1.275A    -21.25mA
-820mV    -70.75mA   -824.4mA   -3.94mA
-700mV    -1.177mA   -169.1mA   -239.8uA
-580mV    -25.2uA    -8.386mA   -7.201uA
2.48V     178pA      15.04nA    165.8pA
[POWER_clamp]
| voltage   I(typ)   I(min)   I(max)
-2.49V    14.32A     15.09A     13.9A
-1.2V     1.938A     2.775A     1.451A
-1.17V    1.676A     2.51A      1.19A
-1.14V    1.419A     2.247A     938.4mA
-1.11V    1.169A     1.989A     698.1mA
-1.05V    700.4mA    1.489A     281.6mA
-1.02V    491.6mA    1.249A     133.5mA
-960mV    168.5mA    801.5mA    13.92mA
-930mV    75.96mA    600.7mA    4.42mA
-840mV    3.915mA    158.9mA    769.8uA
-780mV    843uA      39.78mA    364.7uA
0V        181pA      1.191nA    191.2pA
[Ramp]
| variable   typ   min   max
dV/dt_r   0.2839/7.2876n   60.1978m/6.6356n  0.6835/3.7009n
dV/dt_f   0.3463/5.0576n   0.1160/5.2440n   0.6411/3.8076n
R_load = 50.0000
[Rising Waveform]
R_fixture = 50.0000
V_fixture = 0.000
V_fixture_min = 0.000
V_fixture_max = 0.000
| time   V(typ)   V(min)   V(max)
0s        1.15nV     4.639nV    902.7pV
454.5ps   686.2uV    321.8uV    -11.66mV
1.364ns   72mV       -13.63mV   166.8mV
3.182ns   112mV      68.3mV     215.2mV
7.727ns   282.3mV    73.88mV    991.7mV
10.45ns   497.6mV    106.4mV    1.151V
14.09ns   694.6mV    190.5mV    1.188V
18.64ns   781.5mV    315.1mV    1.191V
28.18ns   805.3mV    471.8mV    1.191V
45ns      806mV      509.9mV    1.191V
[Rising Waveform]
R_fixture = 50.0000
V_fixture = 2.5000
V_fixture_min = 2.3000
V_fixture_max = 2.7000
| time   V(typ)   V(min)   V(max)
0s        1.814V     1.923V     1.605V
383.8ps   1.812V     1.923V     1.625V
444.4ps   1.807V     1.923V     1.742V
565.7ps   1.823V     1.921V     2.212V
626.3ps   1.876V     1.919V     2.378V
707.1ps   2.012V     1.916V     2.516V
828.3ps   2.256V     1.919V     2.616V
1.03ns    2.435V     2.015V     2.673V
1.353ns   2.484V     2.239V     2.689V
2ns       2.496V     2.294V     2.695V
[Falling Waveform]
R_fixture = 50.0000
V_fixture = 0.000
V_fixture_min = 0.000
V_fixture_max = 0.000
| time   V(typ)   V(min)   V(max)
0s        806mV      511.8mV    1.191V
363.6ps   817.2mV    513.2mV    1.177V
424.2ps   820.8mV    516.1mV    1.049V
505.1ps   792.2mV    520.8mV    774.3mV
626.3ps   626.3mV    524.2mV    390.7mV
727.3ps   435.5mV    511.7mV    219.8mV
848.5ps   237.7mV    459.3mV    116mV
1.03ns    83.98mV    299.5mV    44.02mV
1.353ns   21.31mV    82.15mV    11.95mV
2ns       4.335mV    8.062mV    3.256mV
[Falling Waveform]
R_fixture = 50.0000
V_fixture = 2.5000
V_fixture_min = 2.3000
V_fixture_max = 2.7000
| time   V(typ)   V(min)   V(max)
0s        2.5V       2.3V       2.7V
818.2ps   2.529V     2.309V     2.717V
1.636ns   2.483V     2.311V     2.541V
5.727ns   2.202V     2.213V     1.859V
6.818ns   2.114V     2.194V     1.754V
8.182ns   2.018V     2.161V     1.677V
10.64ns   1.904V     2.092V     1.624V
13.91ns   1.839V     2.008V     1.607V
19.09ns   1.817V     1.949V     1.605V
27ns      1.814V     1.926V     1.605V
